VERSION 5.8 ;
BUSBITCHARS "[]" ;
DIVIDERCHAR "/" ;
UNITS
    DATABASE MICRONS 1000 ;
END UNITS

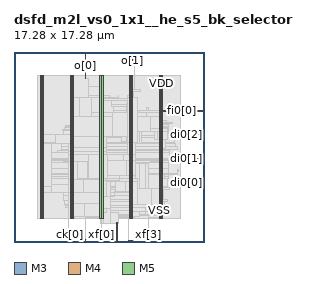
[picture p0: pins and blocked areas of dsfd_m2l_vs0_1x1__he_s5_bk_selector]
MACRO dsfd_m2l_vs0_1x1__he_s5_bk_selector
  FOREIGN dsfd_m2l_vs0_1x1__he_s5_bk_selector 0 0 ;
  CLASS BLOCK ;
  SIZE 17.28 BY 17.28 ;
  PIN ck[0]
    DIRECTION INPUT ;
    USE SIGNAL ;
    PORT
      LAYER M3 ;
        RECT  5.04 0 5.058 0.144 ;
    END
    PORT
      LAYER M3 ;
        RECT  5.04 0.108 5.058 0.557 ;
    END
  END ck[0]
  PIN di0[0]
    DIRECTION INPUT ;
    USE SIGNAL ;
    PORT
      LAYER M4 ;
        RECT  17.088 5.424 17.28 5.448 ;
    END
    PORT
      LAYER M4 ;
        RECT  15.397 5.424 17.1 5.448 ;
    END
  END di0[0]
  PIN di0[1]
    DIRECTION INPUT ;
    USE SIGNAL ;
    PORT
      LAYER M4 ;
        RECT  17.088 7.584 17.28 7.608 ;
    END
    PORT
      LAYER M4 ;
        RECT  16.513 7.584 17.1 7.608 ;
    END
  END di0[1]
  PIN di0[2]
    DIRECTION INPUT ;
    USE SIGNAL ;
    PORT
      LAYER M4 ;
        RECT  17.088 9.744 17.28 9.768 ;
    END
    PORT
      LAYER M4 ;
        RECT  16.513 9.744 17.1 9.768 ;
    END
  END di0[2]
  PIN fi0[0]
    DIRECTION INPUT ;
    USE SIGNAL ;
    PORT
      LAYER M4 ;
        RECT  17.088 11.904 17.28 11.928 ;
    END
    PORT
      LAYER M4 ;
        RECT  13.504 11.904 17.1 11.928 ;
    END
  END fi0[0]
  PIN o[0]
    DIRECTION OUTPUT ;
    USE SIGNAL ;
    PORT
      LAYER M3 ;
        RECT  6.48 17.136 6.498 17.28 ;
    END
    PORT
      LAYER M3 ;
        RECT  6.48 14.909 6.498 17.148 ;
    END
  END o[0]
  PIN o[1]
    DIRECTION OUTPUT ;
    USE SIGNAL ;
    PORT
      LAYER M5 ;
        RECT  10.8 17.088 10.824 17.28 ;
    END
    PORT
      LAYER M5 ;
        RECT  10.8 16.549 10.824 17.104 ;
    END
  END o[1]
  PIN rs[0]
    DIRECTION INPUT ;
    USE SIGNAL ;
    PORT
      LAYER M5 ;
        RECT  6.48 0 6.504 0.192 ;
    END
    PORT
      LAYER M5 ;
        RECT  6.48 0.144 6.504 0.227 ;
    END
  END rs[0]
  PIN xf[0]
    DIRECTION INPUT ;
    USE SIGNAL ;
    PORT
      LAYER M3 ;
        RECT  7.92 0 7.938 0.144 ;
    END
    PORT
      LAYER M3 ;
        RECT  7.92 0.108 7.938 0.173 ;
    END
  END xf[0]
  PIN xf[1]
    DIRECTION INPUT ;
    USE SIGNAL ;
    PORT
      LAYER M5 ;
        RECT  9.36 0 9.384 0.192 ;
    END
    PORT
      LAYER M5 ;
        RECT  9.36 0.144 9.384 1.763 ;
    END
  END xf[1]
  PIN xf[2]
    DIRECTION INPUT ;
    USE SIGNAL ;
    PORT
      LAYER M3 ;
        RECT  10.8 0 10.818 0.144 ;
    END
    PORT
      LAYER M3 ;
        RECT  10.8 0.108 10.818 0.139 ;
    END
    PORT
      LAYER M3 ;
        RECT  10.44 0.139 10.818 0.167 ;
    END
  END xf[2]
  PIN xf[3]
    DIRECTION INPUT ;
    USE SIGNAL ;
    PORT
      LAYER M5 ;
        RECT  12.24 0 12.264 0.192 ;
    END
    PORT
      LAYER M5 ;
        RECT  12.24 0.144 12.264 0.227 ;
    END
  END xf[3]
  PIN VDD
    DIRECTION INOUT ;
    USE POWER ;
    PORT
      LAYER M5 ;
        RECT  13.392 2.151 13.512 15.129 ;
        RECT  10.692 2.151 10.812 15.129 ;
        RECT  7.992 2.151 8.112 15.129 ;
        RECT  5.292 2.151 5.412 15.129 ;
        RECT  2.592 2.151 2.712 15.129 ;
    END
  END VDD
  PIN VSS
    DIRECTION INOUT ;
    USE GROUND ;
    PORT
      LAYER M5 ;
        RECT  13.2 2.137 13.32 15.143 ;
        RECT  10.5 2.137 10.62 15.143 ;
        RECT  7.8 2.137 7.92 15.143 ;
        RECT  5.1 2.137 5.22 15.143 ;
        RECT  2.4 2.137 2.52 15.143 ;
    END
  END VSS
  # OT_OBS_CLOSED layer=M5 d_um=1.536 added=23
  OBS
    LAYER RVTN ;
     RECT  2.16 2.16 15.12 2.295 ;
     RECT  2.16 2.565 15.12 2.835 ;
     RECT  2.16 3.105 15.12 3.375 ;
     RECT  2.16 3.645 15.12 3.915 ;
     RECT  2.16 4.185 15.12 4.455 ;
     RECT  2.16 4.725 15.12 4.995 ;
     RECT  2.16 5.265 15.12 5.535 ;
     RECT  2.16 5.805 15.12 6.075 ;
     RECT  2.16 6.345 15.12 6.615 ;
     RECT  2.16 6.885 15.12 7.155 ;
     RECT  2.16 7.425 15.12 7.695 ;
     RECT  2.16 7.965 15.12 8.235 ;
     RECT  2.16 8.505 15.12 8.775 ;
     RECT  2.16 9.045 15.12 9.315 ;
     RECT  2.16 9.585 15.12 9.855 ;
     RECT  2.16 10.125 15.12 10.395 ;
     RECT  2.16 10.665 15.12 10.935 ;
     RECT  2.16 11.205 15.12 11.475 ;
     RECT  2.16 11.745 15.12 12.015 ;
     RECT  2.16 12.285 15.12 12.555 ;
     RECT  2.16 12.825 15.12 13.095 ;
     RECT  2.16 13.365 15.12 13.635 ;
     RECT  2.16 13.905 15.12 14.175 ;
     RECT  2.16 14.445 15.12 14.715 ;
     RECT  2.16 14.985 15.12 15.12 ;
    LAYER RVTP ;
     RECT  2.16 2.295 15.12 2.565 ;
     RECT  2.16 2.835 15.12 3.105 ;
     RECT  2.16 3.375 15.12 3.645 ;
     RECT  2.16 3.915 15.12 4.185 ;
     RECT  2.16 4.455 15.12 4.725 ;
     RECT  2.16 4.995 15.12 5.265 ;
     RECT  2.16 5.535 15.12 5.805 ;
     RECT  2.16 6.075 15.12 6.345 ;
     RECT  2.16 6.615 15.12 6.885 ;
     RECT  2.16 7.155 15.12 7.425 ;
     RECT  2.16 7.695 15.12 7.965 ;
     RECT  2.16 8.235 15.12 8.505 ;
     RECT  2.16 8.775 15.12 9.045 ;
     RECT  2.16 9.315 15.12 9.585 ;
     RECT  2.16 9.855 15.12 10.125 ;
     RECT  2.16 10.395 15.12 10.665 ;
     RECT  2.16 10.935 15.12 11.205 ;
     RECT  2.16 11.475 15.12 11.745 ;
     RECT  2.16 12.015 15.12 12.285 ;
     RECT  2.16 12.555 15.12 12.825 ;
     RECT  2.16 13.095 15.12 13.365 ;
     RECT  2.16 13.635 15.12 13.905 ;
     RECT  2.16 14.175 15.12 14.445 ;
     RECT  2.16 14.715 15.12 14.985 ;
    LAYER M1 ;
     RECT  2.16 2.151 15.12 15.129 ;
    LAYER M2 ;
     RECT  10.435 0.144 10.823 0.162 ;
     RECT  2.16 2.151 15.12 15.129 ;
     RECT  15.12 5.58 15.431 5.598 ;
     RECT  15.12 7.74 16.547 7.758 ;
     RECT  15.12 10.098 16.547 10.116 ;
    LAYER M3 ;
     RECT  10.44 0.167 10.458 2.143 ;
     RECT  5.115 2.143 5.205 2.191 ;
     RECT  6.48 0.187 6.498 2.191 ;
     RECT  7.815 2.143 7.905 2.191 ;
     RECT  8.82 1.723 9.45 2.191 ;
     RECT  10.44 2.143 10.605 2.191 ;
     RECT  12.24 0.187 12.258 2.191 ;
     RECT  13.215 2.143 13.305 2.191 ;
     RECT  10.44 2.191 10.674 2.227 ;
     RECT  8.82 2.191 9.558 2.263 ;
     RECT  10.44 2.227 10.926 2.263 ;
     RECT  8.82 2.263 10.926 2.293 ;
     RECT  5.115 2.191 5.49 2.299 ;
     RECT  5.115 2.299 5.742 2.335 ;
     RECT  6.48 2.191 7.905 2.335 ;
     RECT  5.115 2.335 7.905 2.371 ;
     RECT  8.82 2.293 11.43 2.371 ;
     RECT  12.24 2.191 13.305 2.371 ;
     RECT  2.415 2.143 2.505 2.413 ;
     RECT  5.115 2.371 13.305 2.413 ;
     RECT  5.115 2.413 13.497 2.533 ;
     RECT  5.076 2.533 13.497 2.875 ;
     RECT  5.076 2.875 13.662 3.145 ;
     RECT  4.68 3.145 13.662 3.335 ;
     RECT  4.68 3.335 6.534 3.415 ;
     RECT  7.272 3.335 13.662 3.721 ;
     RECT  4.572 3.415 6.534 3.811 ;
     RECT  7.272 3.721 13.986 3.839 ;
     RECT  4.464 3.811 6.534 4.225 ;
     RECT  7.272 3.839 13.554 4.225 ;
     RECT  3.6 4.495 3.618 4.531 ;
     RECT  4.464 4.225 13.554 4.531 ;
     RECT  3.6 4.531 13.554 4.801 ;
     RECT  3.42 4.801 14.166 4.919 ;
     RECT  2.415 2.413 2.697 5.071 ;
     RECT  3.42 4.919 13.986 5.071 ;
     RECT  15.408 5.419 15.426 5.603 ;
     RECT  2.415 5.071 13.986 5.755 ;
     RECT  2.415 5.755 14.058 5.789 ;
     RECT  3.42 5.789 14.058 5.971 ;
     RECT  3.42 5.971 14.094 6.151 ;
     RECT  3.42 6.151 14.85 6.269 ;
     RECT  14.832 6.269 14.85 6.421 ;
     RECT  14.832 6.421 14.922 6.539 ;
     RECT  14.904 6.539 14.922 6.575 ;
     RECT  2.415 5.789 2.697 6.691 ;
     RECT  3.42 6.269 14.094 6.691 ;
     RECT  2.415 6.691 14.094 7.223 ;
     RECT  3.42 7.223 14.094 7.393 ;
     RECT  3.42 7.393 14.166 7.531 ;
     RECT  3.42 7.531 14.274 7.619 ;
     RECT  16.524 7.579 16.542 7.763 ;
     RECT  2.415 7.223 2.697 8.155 ;
     RECT  3.42 7.619 14.166 8.155 ;
     RECT  2.415 8.155 14.166 8.159 ;
     RECT  2.415 8.159 3.114 8.231 ;
     RECT  3.96 8.159 14.166 8.303 ;
     RECT  4.356 8.303 14.166 8.401 ;
     RECT  4.356 8.401 14.85 8.699 ;
     RECT  4.356 8.699 14.67 8.969 ;
     RECT  4.356 8.969 14.562 9.011 ;
     RECT  4.536 9.011 14.562 9.545 ;
     RECT  4.536 9.545 14.274 9.677 ;
     RECT  4.536 9.677 8.766 9.739 ;
     RECT  9.504 9.677 14.274 9.779 ;
     RECT  3.816 9.739 8.766 9.815 ;
     RECT  9.504 9.779 14.13 9.815 ;
     RECT  16.524 9.739 16.542 10.121 ;
     RECT  4.464 9.815 8.766 10.205 ;
     RECT  4.608 10.205 8.766 10.391 ;
     RECT  4.716 10.391 8.766 10.435 ;
     RECT  9.504 9.815 14.022 10.435 ;
     RECT  4.716 10.435 14.022 10.493 ;
     RECT  4.716 10.493 8.622 10.625 ;
     RECT  9.612 10.493 14.022 10.705 ;
     RECT  9.612 10.705 14.094 10.741 ;
     RECT  9.612 10.741 14.382 10.895 ;
     RECT  9.612 10.895 13.842 11.039 ;
     RECT  9.612 11.039 13.497 11.227 ;
     RECT  5.115 10.625 8.514 11.273 ;
     RECT  9.54 11.227 13.497 11.371 ;
     RECT  5.115 11.273 8.262 11.453 ;
     RECT  9.072 11.371 13.497 11.939 ;
     RECT  9.072 11.939 12.222 11.981 ;
     RECT  12.06 11.981 12.222 12.209 ;
     RECT  12.06 12.209 12.078 12.245 ;
     RECT  9.072 11.981 11.07 12.289 ;
     RECT  9.036 12.289 11.07 12.325 ;
     RECT  8.892 12.325 11.07 12.479 ;
     RECT  5.115 11.453 8.154 12.551 ;
     RECT  6.372 12.551 8.154 12.587 ;
     RECT  6.732 12.587 8.154 12.859 ;
     RECT  8.892 12.479 10.89 12.859 ;
     RECT  6.732 12.859 10.89 13.055 ;
     RECT  6.732 13.055 9.522 13.163 ;
     RECT  6.732 13.163 8.73 13.289 ;
     RECT  9.504 13.163 9.522 13.289 ;
     RECT  6.732 13.289 8.586 13.325 ;
     RECT  10.515 13.055 10.89 13.711 ;
     RECT  10.515 13.711 11.466 13.865 ;
     RECT  6.732 13.325 8.097 14.135 ;
     RECT  2.415 8.231 2.697 14.867 ;
     RECT  5.115 12.551 5.397 14.867 ;
     RECT  7.815 14.135 8.097 14.867 ;
     RECT  13.215 11.939 13.497 14.867 ;
     RECT  6.732 14.135 6.75 14.881 ;
     RECT  6.48 14.881 6.75 14.909 ;
     RECT  2.415 14.867 2.505 15.137 ;
     RECT  5.115 14.867 5.205 15.137 ;
     RECT  7.815 14.867 7.905 15.137 ;
     RECT  10.515 13.865 10.962 15.137 ;
     RECT  13.215 14.867 13.305 15.137 ;
     RECT  10.944 15.137 10.962 16.589 ;
    LAYER M4 ;
     RECT  2.408 2.148 2.512 15.132 ;
     RECT  2.512 2.418 2.704 14.862 ;
     RECT  2.704 4.512 3.395 5.784 ;
     RECT  2.704 8.16 3.395 9 ;
     RECT  2.704 7.152 3.436 7.176 ;
     RECT  3.395 8.976 3.781 9 ;
     RECT  3.781 8.976 3.868 9.768 ;
     RECT  4.525 7.344 4.933 7.368 ;
     RECT  3.868 8.976 4.933 9 ;
     RECT  4.933 0.528 5.069 0.552 ;
     RECT  3.395 4.512 5.108 5.208 ;
     RECT  4.933 7.344 5.108 9 ;
     RECT  4.453 10.176 5.108 10.2 ;
     RECT  5.108 2.148 5.212 15.132 ;
     RECT  5.212 2.304 5.404 14.862 ;
     RECT  5.404 3.504 5.537 10.776 ;
     RECT  5.537 5.664 5.717 10.776 ;
     RECT  5.537 3.504 6.401 4.536 ;
     RECT  6.401 3.504 6.419 4.152 ;
     RECT  5.717 5.664 6.545 8.232 ;
     RECT  6.469 0.192 6.553 0.216 ;
     RECT  5.717 9.6 6.653 10.776 ;
     RECT  6.653 10.752 6.853 10.776 ;
     RECT  6.545 5.76 6.997 8.232 ;
     RECT  6.853 9.552 6.997 9.576 ;
     RECT  5.404 13.104 7.117 13.128 ;
     RECT  6.853 10.752 7.369 11.448 ;
     RECT  6.419 4.128 7.405 4.152 ;
     RECT  7.405 4.128 7.477 4.2 ;
     RECT  5.404 2.304 7.808 2.328 ;
     RECT  7.477 4.128 7.808 4.248 ;
     RECT  6.997 5.76 7.808 9.576 ;
     RECT  7.369 10.752 7.808 11.544 ;
     RECT  7.117 12.864 7.808 13.128 ;
     RECT  7.808 2.148 7.909 15.132 ;
     RECT  7.909 1.728 7.912 15.132 ;
     RECT  7.868 0.144 7.955 0.168 ;
     RECT  7.912 1.728 8.104 14.862 ;
     RECT  8.104 5.616 8.237 11.784 ;
     RECT  8.237 9.552 8.291 11.784 ;
     RECT  8.237 5.616 8.387 8.568 ;
     RECT  8.387 5.616 8.705 7.992 ;
     RECT  8.104 1.728 8.819 3.096 ;
     RECT  8.104 12.864 8.849 12.888 ;
     RECT  8.291 9.552 9.065 10.488 ;
     RECT  8.104 4.128 9.097 4.152 ;
     RECT  9.097 4.128 9.137 4.584 ;
     RECT  9.137 4.56 9.205 4.584 ;
     RECT  8.705 5.616 9.205 6.408 ;
     RECT  8.819 1.728 9.461 2.712 ;
     RECT  8.291 11.76 9.529 11.784 ;
     RECT  9.065 9.552 9.817 9.96 ;
     RECT  8.705 7.968 9.925 7.992 ;
     RECT  9.205 4.56 10.177 6.408 ;
     RECT  9.925 7.392 10.177 7.992 ;
     RECT  9.817 9.12 10.213 9.96 ;
     RECT  9.529 11.232 10.249 11.784 ;
     RECT  10.213 8.976 10.296 9.96 ;
     RECT  10.249 11.232 10.296 12.552 ;
     RECT  10.296 8.976 10.309 12.552 ;
     RECT  9.461 2.496 10.465 2.52 ;
     RECT  10.465 2.496 10.508 3.336 ;
     RECT  10.177 4.56 10.508 7.992 ;
     RECT  10.309 8.976 10.508 13.32 ;
     RECT  10.508 2.148 10.612 15.132 ;
     RECT  10.612 2.304 10.804 14.862 ;
     RECT  10.789 16.56 10.973 16.584 ;
     RECT  10.804 8.544 11.053 10.728 ;
     RECT  10.804 13.104 11.267 13.128 ;
     RECT  11.053 8.976 11.405 10.728 ;
     RECT  10.804 2.304 11.441 7.128 ;
     RECT  10.804 11.76 11.441 11.976 ;
     RECT  11.405 8.976 11.621 10.104 ;
     RECT  11.441 2.496 11.945 7.128 ;
     RECT  11.945 2.784 11.989 7.128 ;
     RECT  11.441 11.76 12.085 11.784 ;
     RECT  11.989 3.12 12.197 7.128 ;
     RECT  12.229 0.192 12.313 0.216 ;
     RECT  11.621 9.648 12.805 10.104 ;
     RECT  12.805 9.36 13.057 10.104 ;
     RECT  12.197 3.12 13.208 6.12 ;
     RECT  12.409 7.344 13.208 7.368 ;
     RECT  13.057 9.36 13.208 10.2 ;
     RECT  12.085 11.424 13.208 11.784 ;
     RECT  13.208 2.148 13.312 15.132 ;
     RECT  13.312 2.418 13.504 14.862 ;
     RECT  13.504 5.76 13.709 6.12 ;
     RECT  13.504 8.544 13.745 10.296 ;
     RECT  13.745 9.36 13.955 10.296 ;
     RECT  13.955 9.36 13.997 10.2 ;
     RECT  13.997 10.176 14.033 10.2 ;
     RECT  13.709 5.76 14.069 5.784 ;
     RECT  13.504 7.536 14.285 7.56 ;
    LAYER M5 ;
     RECT  4.944 0.517 4.968 2.137 ;
     RECT  7.92 0.133 7.944 2.137 ;
     RECT  2.4 2.137 2.52 2.151 ;
     RECT  4.944 2.137 5.22 2.151 ;
     RECT  7.8 2.137 7.944 2.151 ;
     RECT  10.5 2.137 10.62 2.151 ;
     RECT  13.2 2.137 13.32 2.151 ;
     RECT  7.8 2.151 8.112 2.677 ;
     RECT  7.8 2.677 8.376 3.061 ;
     RECT  11.952 2.773 11.976 3.109 ;
     RECT  13.2 2.151 13.512 3.109 ;
     RECT  10.5 2.151 10.812 3.157 ;
     RECT  11.952 3.109 13.512 3.157 ;
     RECT  10.5 3.157 13.512 3.443 ;
     RECT  6.384 2.293 6.408 3.539 ;
     RECT  7.8 3.061 8.808 4.163 ;
     RECT  4.944 2.151 5.412 4.501 ;
     RECT  12.48 3.443 13.512 4.835 ;
     RECT  2.4 2.151 2.712 5.077 ;
     RECT  10.5 3.443 11.256 5.509 ;
     RECT  7.8 4.163 8.376 5.605 ;
     RECT  4.944 4.501 6.312 5.699 ;
     RECT  9.6 5.509 11.256 5.795 ;
     RECT  7.8 5.605 8.424 5.797 ;
     RECT  9.6 5.795 11.016 6.035 ;
     RECT  4.944 5.699 5.736 7.333 ;
     RECT  6.72 5.749 6.744 7.333 ;
     RECT  10.272 6.035 11.016 7.381 ;
     RECT  4.944 7.333 6.744 7.957 ;
     RECT  7.8 5.797 8.52 7.957 ;
     RECT  4.944 7.957 8.52 8.003 ;
     RECT  9.936 7.381 11.016 8.003 ;
     RECT  4.944 8.003 8.376 8.243 ;
     RECT  5.1 8.243 8.376 8.579 ;
     RECT  2.4 5.077 3.384 8.965 ;
     RECT  2.4 8.965 3.816 9.011 ;
     RECT  10.32 8.003 11.016 9.013 ;
     RECT  13.2 4.835 13.512 9.349 ;
     RECT  5.1 8.579 8.112 9.637 ;
     RECT  3.792 9.011 3.816 9.779 ;
     RECT  13.2 9.349 13.944 10.069 ;
     RECT  12.384 10.069 13.944 10.307 ;
     RECT  5.1 9.637 8.952 11.459 ;
     RECT  12.384 10.307 13.512 11.459 ;
     RECT  7.008 11.459 8.952 11.795 ;
     RECT  5.1 11.459 5.976 13.139 ;
     RECT  7.008 11.795 8.112 13.139 ;
     RECT  10.32 9.013 11.256 13.139 ;
     RECT  10.32 13.139 10.812 13.331 ;
     RECT  2.4 9.011 2.712 15.129 ;
     RECT  5.1 13.139 5.412 15.129 ;
     RECT  7.8 13.139 8.112 15.129 ;
     RECT  10.5 13.331 10.812 15.129 ;
     RECT  13.2 11.459 13.512 15.129 ;
     RECT  2.4 15.129 2.52 15.143 ;
     RECT  5.1 15.129 5.22 15.143 ;
     RECT  7.8 15.129 7.92 15.143 ;
     RECT  10.5 15.129 10.62 15.143 ;
     RECT  13.2 15.129 13.32 15.143 ;
     RECT  5.412 2.293 6.384 3.539 ;
     RECT  6.408 2.293 7.8 3.539 ;
     RECT  10.812 2.773 11.952 3.157 ;
     RECT  11.976 2.773 13.2 3.109 ;
     RECT  11.256 3.443 12.48 4.835 ;
     RECT  5.412 3.539 7.8 4.501 ;
     RECT  8.376 4.163 8.808 5.509 ;
     RECT  6.312 4.501 7.8 5.699 ;
     RECT  8.376 5.509 9.6 5.605 ;
     RECT  8.424 5.605 9.6 5.797 ;
     RECT  5.736 5.699 7.8 5.749 ;
     RECT  5.736 5.749 6.72 7.333 ;
     RECT  6.744 5.749 7.8 7.957 ;
     RECT  8.52 5.797 9.6 6.035 ;
     RECT  8.52 6.035 10.272 7.381 ;
     RECT  8.52 7.381 9.936 8.003 ;
     RECT  4.944 8.243 5.1 8.965 ;
     RECT  8.112 8.579 8.376 9.637 ;
     RECT  3.816 8.965 5.1 9.779 ;
     RECT  2.712 9.011 3.792 9.779 ;
     RECT  8.952 9.637 10.32 11.795 ;
     RECT  11.256 10.069 12.384 11.459 ;
     RECT  5.976 11.459 7.008 13.139 ;
  END
END dsfd_m2l_vs0_1x1__he_s5_bk_selector
END LIBRARY
